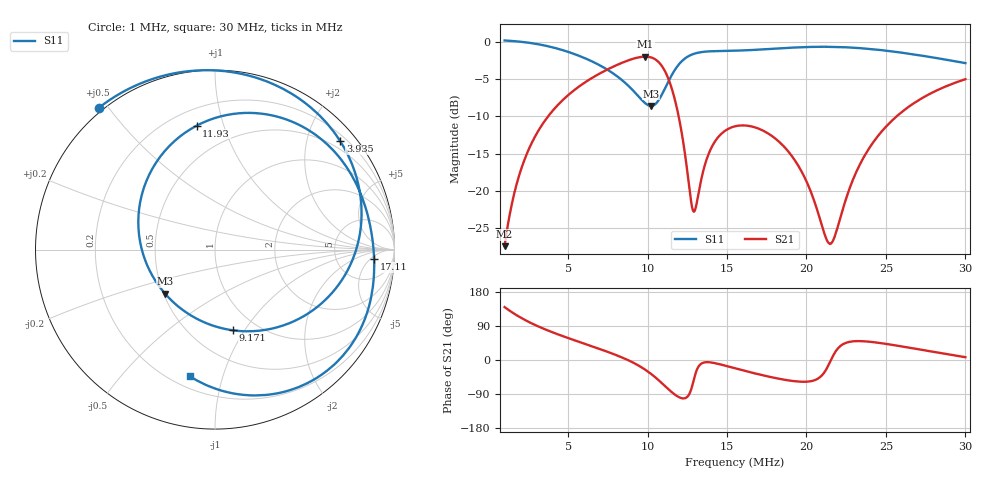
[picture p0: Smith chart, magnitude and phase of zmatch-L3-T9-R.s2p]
# HZ S RI R 50
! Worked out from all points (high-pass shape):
!   505 points, 1 MHz to 30 MHz, reference 50 ohm
!   highest |S21| = -1.99 dB at 9.861 MHz (marker M1); lowest = -27.4 dB at 1 MHz (marker M2)
!   |S21| within 3 dB of the highest: 6.394 MHz to 11.31 MHz (4.917 MHz wide, 55.5 % of centre)
!   lowest |S11| = -8.6 dB at 10.21 MHz (marker M3), VSWR 2.18, Z = 25.5 - j14.5 ohm
!   |S11| at or under -10 dB: nowhere
!   S12 and S22 are empty: the file has one direction only
!   S11 on the Smith chart (normalised r, x): 1 MHz: -0.01, +0.47; 3.935 MHz: 0.32, +2.65; 9.171 MHz: 0.78, -0.89; 11.93 MHz: 0.30, +0.82; 17.11 MHz: 14, -7; 30 MHz: 0.27, -0.79
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1000000  -0.6485 0.789  -0.0324 0.0276  0 0  0 0
1632940  -0.2775 0.971  -0.0513 0.0843  0 0  0 0
2265880  0.0835 0.9904  -0.0449 0.1569  0 0  0 0
3934540  0.6977 0.6042  0.0903 0.3236  0 0  0 0
5833360  0.7936 0.0251  0.359 0.3685  0 0  0 0
7674640  0.5198 -0.3552  0.6338 0.2126  0 0  0 0
9170680  0.1007 -0.4498  0.7654 -0.1166  0 0  0 0
9861160  -0.1531 -0.3548  0.7155 -0.3479  0 0  0 0
1.02064e7  -0.2775 -0.2463  0.6336 -0.466  0 0  0 0
1.066672e7  -0.4012 -0.0234  0.45 -0.5822  0 0  0 0
1.129966e7  -0.3831 0.3802  0.1305 -0.5523  0 0  0 0
1.19326e7  -0.1018 0.6908  -0.0405 -0.3215  0 0  0 0
1.291078e7  0.42 0.7166  0.0451 -0.0566  0 0  0 0
1.400404e7  0.7189 0.4801  0.1924 -0.022  0 0  0 0
1.550008e7  0.8514 0.1892  0.2516 -0.1007  0 0  0 0
1.71112e7  0.8864 -0.0512  0.2007 -0.1622  0 0  0 0
1.895248e7  0.8635 -0.2943  0.1039 -0.1449  0 0  0 0
2.033344e7  0.8002 -0.463  0.0538 -0.078  0 0  0 0
2.154178e7  0.7112 -0.5926  0.0443 0.0002  0 0  0 0
2.326798e7  0.5411 -0.7299  0.0925 0.1099  0 0  0 0
2.51668e7  0.3271 -0.8044  0.2106 0.1862  0 0  0 0
3.000016e7  -0.1398 -0.7059  0.5567 0.0723  0 0  0 0
